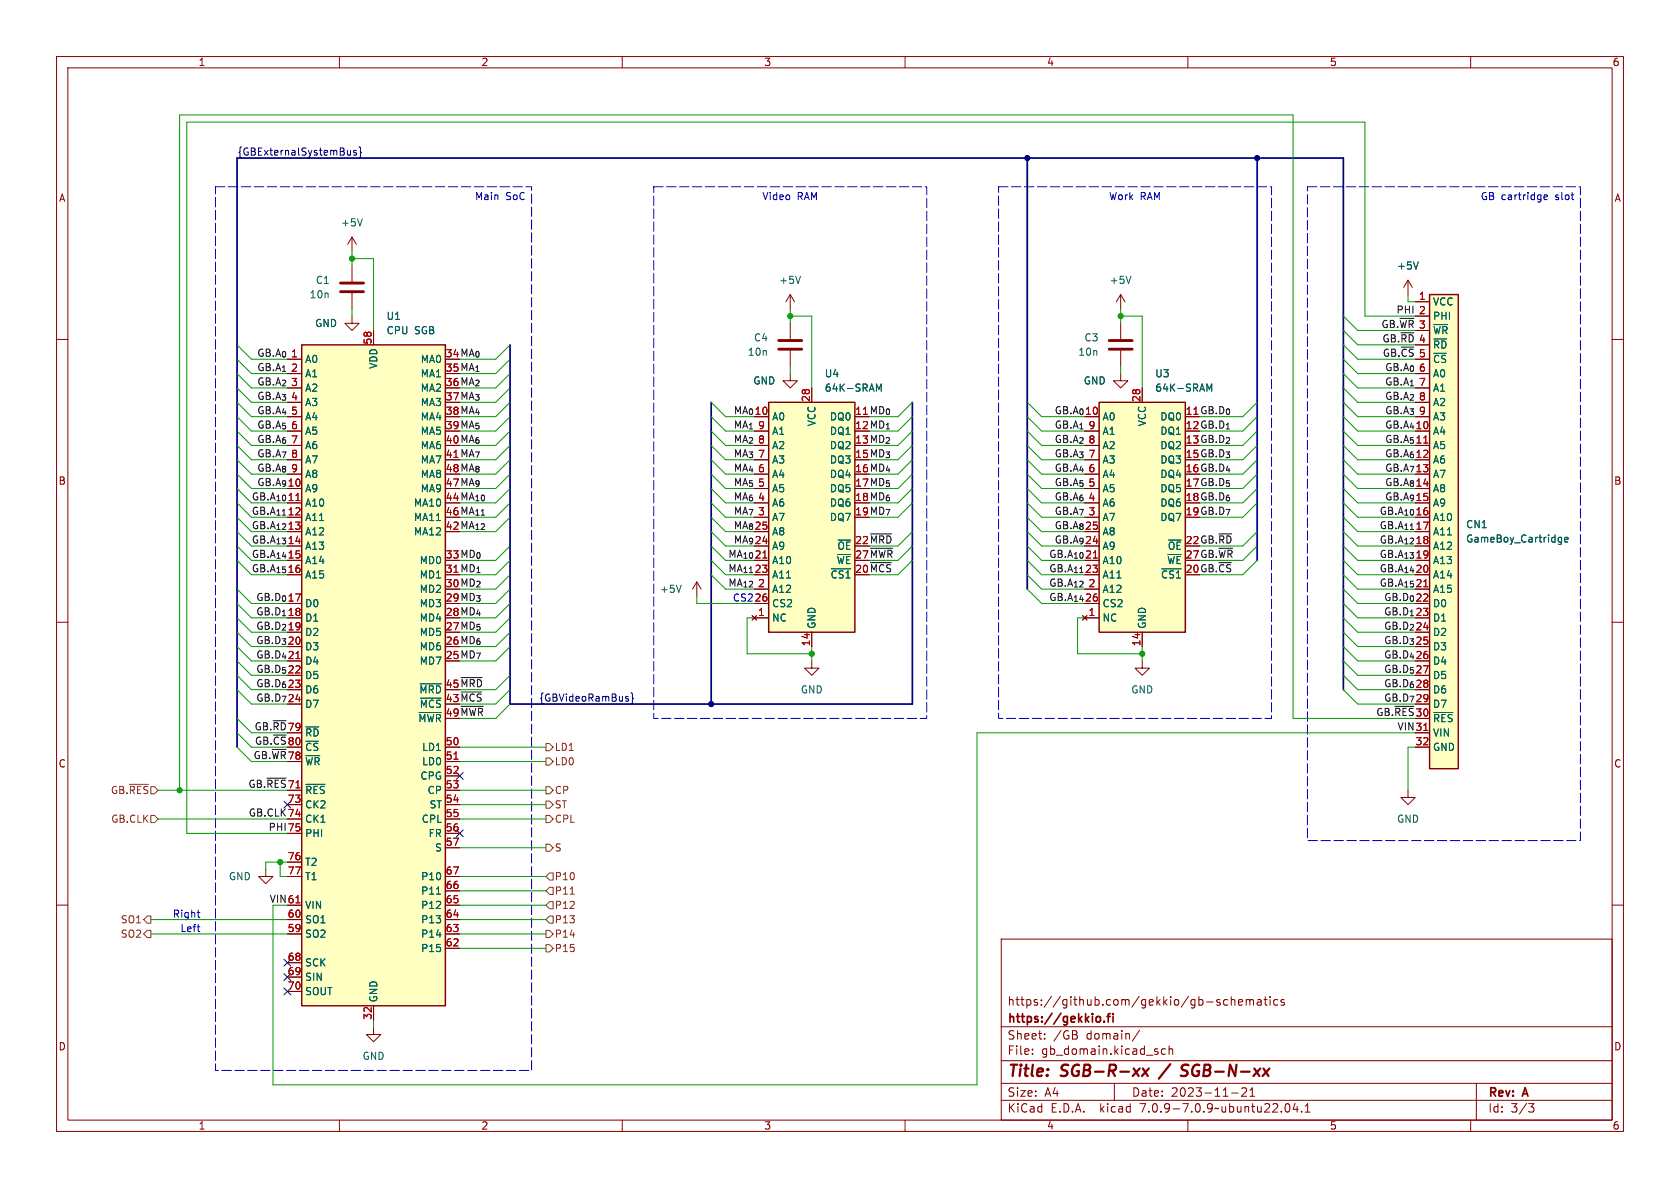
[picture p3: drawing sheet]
<svg xmlns="http://www.w3.org/2000/svg" width="297mm" height="210mm" viewBox="0 0 297 210" stroke-linecap="round" stroke-linejoin="round" font-family="sans-serif">
<defs><g id="words">
<g font-size="2.8" fill="#840000">
<text x="178" y="190.9">Title:</text>
<text x="187.7" y="190.9">SGB-R-xx</text>
<text x="210.5" y="190.9">SGB-N-xx</text>
</g>
<g font-size="2.1" fill="#840000">
<text x="178" y="178">https://github.com/gekkio/gb-schematics</text>
<text x="178" y="184">Sheet:</text>
<text x="178" y="181.2">https://gekkio.fi</text>
<text x="186.2" y="184">/GB</text>
<text x="192.1" y="184">domain/</text>
<text x="178" y="186.7">File:</text>
<text x="184.1" y="186.7">gb_domain.kicad_sch</text>
<text x="178" y="196.9">KiCad</text>
<text x="178" y="194.1">Size:</text>
<text x="184.7" y="194.1">A4</text>
<text x="185.7" y="196.9">E.D.A.</text>
<text x="194.6" y="196.9">kicad</text>
<text x="200" y="194.1">Date:</text>
<text x="201.8" y="196.9">7.0.9-7.0.9~ubuntu22.04.1</text>
<text x="207" y="194.1">2023-11-21</text>
<text x="263" y="194.3">Rev:</text>
<text x="263" y="196.9">Id:</text>
<text x="267.1" y="196.9">3/3</text>
<text x="269.4" y="194.3">A</text>
</g>
<g font-size="1.8" fill="#840000">
<text x="35" y="11.9">1</text>
<text x="85" y="11.9">2</text>
<text x="135" y="11.9">3</text>
<text x="185" y="11.9">4</text>
<text x="235" y="11.9">5</text>
<text x="285" y="11.9">6</text>
<text x="10.3" y="35.9">A</text>
<text x="285.3" y="35.9">A</text>
<text x="244.1" y="58.1">GB.~{WR}</text>
<text x="78.7" y="63.2">34 MA_{0}</text>
<text x="78.7" y="65.8">35 MA_{1}</text>
<text x="78.7" y="68.3">36 MA_{2}</text>
<text x="78.7" y="70.9">37 MA_{3}</text>
<text x="78.7" y="73.4">38 MA_{4}</text>
<text x="78.7" y="75.9">39 MA_{5}</text>
<text x="129.6" y="75.9">MA_{1}</text>
<text x="129.6" y="73.3">MA_{0}</text>
<text x="151.1" y="75.9">12 MD_{1}</text>
<text x="209.5" y="75.9">12 GB.D_{1}</text>
<text x="78.7" y="78.5">40 MA_{6}</text>
<text x="78.7" y="83.6">48 MA_{8}</text>
<text x="129.6" y="80.9">MA_{3}</text>
<text x="129.6" y="83.5">MA_{4}</text>
<text x="129.6" y="78.4">MA_{2}</text>
<text x="151.1" y="78.5">13 MD_{2}</text>
<text x="151.1" y="81">15 MD_{3}</text>
<text x="151.1" y="83.6">16 MD_{4}</text>
<text x="209.5" y="78.5">13 GB.D_{2}</text>
<text x="209.5" y="81">15 GB.D_{3}</text>
<text x="209.5" y="83.6">16 GB.D_{4}</text>
<text x="10.3" y="85.9">B</text>
<text x="78.7" y="88.6">44 MA_{10}</text>
<text x="78.7" y="86.1">47 MA_{9}</text>
<text x="129.6" y="86">MA_{5}</text>
<text x="129.6" y="88.6">MA_{6}</text>
<text x="151.1" y="86.1">17 MD_{5}</text>
<text x="151.1" y="88.6">18 MD_{6}</text>
<text x="209.5" y="86.1">17 GB.D_{5}</text>
<text x="209.5" y="88.6">18 GB.D_{6}</text>
<text x="285.3" y="85.9">B</text>
<text x="78.7" y="93.7">42 MA_{12}</text>
<text x="78.7" y="91.2">46 MA_{11}</text>
<text x="129.6" y="91.1">MA_{7}</text>
<text x="129.6" y="93.6">MA_{8}</text>
<text x="151.1" y="91.2">19 MD_{7}</text>
<text x="209.5" y="91.2">19 GB.D_{7}</text>
<text x="78.7" y="98.8">33 MD_{0}</text>
<text x="128.6" y="101.3">MA_{11}</text>
<text x="129.6" y="96.2">MA_{9}</text>
<text x="151.1" y="101.3">20 ~{MCS}</text>
<text x="151.1" y="96.3">22 ~{MRD}</text>
<text x="151.1" y="98.8">27 ~{MWR}</text>
<text x="209.5" y="101.3">20 GB.~{CS}</text>
<text x="209.5" y="96.3">22 GB.~{RD}</text>
<text x="209.5" y="98.8">27 GB.~{WR}</text>
<text x="78.7" y="106.4">29 MD_{3}</text>
<text x="78.7" y="103.9">30 MD_{2}</text>
<text x="128.6" y="103.8">MA_{12}</text>
<text x="78.7" y="111.5">27 MD_{5}</text>
<text x="78.7" y="109">28 MD_{4}</text>
<text x="78.7" y="116.6">25 MD_{7}</text>
<text x="78.7" y="114">26 MD_{6}</text>
<text x="78.7" y="124.2">43 ~{MCS}</text>
<text x="78.7" y="121.7">45 ~{MRD}</text>
<text x="78.7" y="126.7">49 ~{MWR}</text>
<text x="10.3" y="135.9">C</text>
<text x="44.7" y="134.3">GB.~{WR}</text>
<text x="285.3" y="135.9">C</text>
<text x="10.3" y="185.9">D</text>
<text x="285.3" y="185.9">D</text>
<text x="35" y="199.9">1</text>
<text x="85" y="199.9">2</text>
<text x="135" y="199.9">3</text>
<text x="185" y="199.9">4</text>
<text x="235" y="199.9">5</text>
<text x="285" y="199.9">6</text>
</g>
<g font-size="1.8" fill="#000084">
<text x="41.9" y="27.6">{GBExternalSystemBus}</text>
<text x="95.2" y="124.1">{GBVideoRamBus}</text>
</g>
<g font-size="1.8" fill="#0000c2">
<text x="83.9" y="35.7">Main</text>
<text x="89.4" y="35.7">SoC</text>
<text x="134.7" y="35.7">Video</text>
<text x="140.9" y="35.7">RAM</text>
<text x="196" y="35.7">Work</text>
<text x="201.5" y="35.7">RAM</text>
<text x="261.7" y="35.7">GB cartridge</text>
<text x="275.1" y="35.7">slot</text>
<text x="129.5" y="106.4">CS2</text>
<text x="30.5" y="162.3">Right</text>
<text x="31.8" y="164.9">Left</text>
</g>
<g font-size="1.8" fill="#006464">
<text x="60.2" y="40.2">+5V</text>
<text x="246.9" y="47.9">+5V</text>
<text x="54.6" y="52.9">10n</text>
<text x="55.7" y="50.4">C1</text>
<text x="137.7" y="50.4">+5V</text>
<text x="196.1" y="50.4">+5V</text>
<text x="55.6" y="58">GND</text>
<text x="68.2" y="56.7">U1</text>
<text x="68.2" y="59.3">CPU</text>
<text x="73.3" y="59.3">SGB</text>
<text x="253.2" y="54.2">VCC</text>
<text x="253.2" y="56.7">PHI</text>
<text x="253.2" y="59.3">~{WR}</text>
<text x="53.8" y="64.4">A0</text>
<text x="66.9" y="65.3" transform="rotate(-90 66.9 65.3)">VDD</text>
<text x="74.3" y="64.4">MA0</text>
<text x="132.1" y="63.1">10n</text>
<text x="133.2" y="60.6">C4</text>
<text x="190.5" y="63.1">10n</text>
<text x="191.6" y="60.6">C3</text>
<text x="253.2" y="61.8">~{RD}</text>
<text x="253.2" y="64.4">~{CS}</text>
<text x="53.8" y="66.9">A1</text>
<text x="53.8" y="69.4">A2</text>
<text x="53.8" y="72">A3</text>
<text x="74.3" y="66.9">MA1</text>
<text x="74.3" y="69.4">MA2</text>
<text x="74.3" y="72">MA3</text>
<text x="133.1" y="68.2">GND</text>
<text x="145.7" y="66.9">U4</text>
<text x="145.7" y="69.4">64K-SRAM</text>
<text x="191.5" y="68.2">GND</text>
<text x="204.1" y="66.9">U3</text>
<text x="204.1" y="69.4">64K-SRAM</text>
<text x="253.2" y="66.9">A0</text>
<text x="253.2" y="69.4">A1</text>
<text x="253.2" y="72">A2</text>
<text x="53.8" y="74.5">A4</text>
<text x="53.8" y="77.1">A5</text>
<text x="74.3" y="74.5">MA4</text>
<text x="74.3" y="77.1">MA5</text>
<text x="136.4" y="74.5">A0</text>
<text x="136.4" y="77.1">A1</text>
<text x="144.4" y="75.5" transform="rotate(-90 144.4 75.5)">VCC</text>
<text x="146.6" y="74.5">DQ0</text>
<text x="146.6" y="77.1">DQ1</text>
<text x="194.8" y="74.5">A0</text>
<text x="194.8" y="77.1">A1</text>
<text x="202.8" y="75.5" transform="rotate(-90 202.8 75.5)">VCC</text>
<text x="205" y="74.5">DQ0</text>
<text x="205" y="77.1">DQ1</text>
<text x="253.2" y="77.1">A4</text>
<text x="253.2" y="74.5">A3</text>
<text x="53.8" y="79.6">A6</text>
<text x="53.8" y="82.1">A7</text>
<text x="74.3" y="79.6">MA6</text>
<text x="74.3" y="82.1">MA7</text>
<text x="136.4" y="82.1">A3</text>
<text x="136.4" y="79.6">A2</text>
<text x="146.6" y="79.6">DQ2</text>
<text x="146.6" y="82.1">DQ3</text>
<text x="194.8" y="82.1">A3</text>
<text x="194.8" y="79.6">A2</text>
<text x="205" y="79.6">DQ2</text>
<text x="205" y="82.1">DQ3</text>
<text x="253.2" y="79.6">A5</text>
<text x="253.2" y="82.1">A6</text>
<text x="53.8" y="87.2">A9</text>
<text x="53.8" y="89.8">A10</text>
<text x="53.8" y="84.7">A8</text>
<text x="73.1" y="89.8">MA10</text>
<text x="74.3" y="87.2">MA9</text>
<text x="74.3" y="84.7">MA8</text>
<text x="136.4" y="89.8">A6</text>
<text x="136.4" y="87.2">A5</text>
<text x="136.4" y="84.7">A4</text>
<text x="146.6" y="84.7">DQ4</text>
<text x="146.6" y="87.2">DQ5</text>
<text x="146.6" y="89.8">DQ6</text>
<text x="194.8" y="89.8">A6</text>
<text x="194.8" y="87.2">A5</text>
<text x="194.8" y="84.7">A4</text>
<text x="205" y="84.7">DQ4</text>
<text x="205" y="87.2">DQ5</text>
<text x="205" y="89.8">DQ6</text>
<text x="253.2" y="84.7">A7</text>
<text x="253.2" y="87.2">A8</text>
<text x="253.2" y="89.8">A9</text>
<text x="53.8" y="92.3">A11</text>
<text x="53.8" y="94.8">A12</text>
<text x="73.1" y="94.8">MA12</text>
<text x="73.1" y="92.3">MA11</text>
<text x="136.4" y="94.8">A8</text>
<text x="136.4" y="92.3">A7</text>
<text x="146.6" y="92.3">DQ7</text>
<text x="194.8" y="94.8">A8</text>
<text x="194.8" y="92.3">A7</text>
<text x="205" y="92.3">DQ7</text>
<text x="253.2" y="92.3">A10</text>
<text x="253.2" y="94.8">A11</text>
<text x="259.1" y="93.6">CN1</text>
<text x="53.8" y="97.4">A13</text>
<text x="53.8" y="99.9">A14</text>
<text x="74.1" y="99.9">MD0</text>
<text x="136.4" y="99.9">A10</text>
<text x="136.4" y="97.4">A9</text>
<text x="147.8" y="99.9">~{WE}</text>
<text x="147.9" y="97.4">~{OE}</text>
<text x="194.8" y="99.9">A10</text>
<text x="194.8" y="97.4">A9</text>
<text x="206.2" y="99.9">~{WE}</text>
<text x="206.4" y="97.4">~{OE}</text>
<text x="253.2" y="97.4">A12</text>
<text x="253.2" y="99.9">A13</text>
<text x="259.1" y="96.1">GameBoy_Cartridge</text>
<text x="53.8" y="102.5">A15</text>
<text x="53.8" y="107.5">D0</text>
<text x="74.1" y="107.5">MD3</text>
<text x="74.1" y="105">MD2</text>
<text x="74.1" y="102.5">MD1</text>
<text x="116.6" y="105">+5V</text>
<text x="136.4" y="105">A12</text>
<text x="136.4" y="102.5">A11</text>
<text x="136.4" y="107.5">CS2</text>
<text x="146.7" y="102.5">~{CS1}</text>
<text x="194.8" y="105">A12</text>
<text x="194.8" y="102.5">A11</text>
<text x="194.8" y="107.5">CS2</text>
<text x="205.1" y="102.5">~{CS1}</text>
<text x="253.2" y="102.5">A14</text>
<text x="253.2" y="105">A15</text>
<text x="253.2" y="107.5">D0</text>
<text x="53.8" y="110.1">D1</text>
<text x="53.8" y="112.6">D2</text>
<text x="74.1" y="112.6">MD5</text>
<text x="74.1" y="110.1">MD4</text>
<text x="136.4" y="110.1">NC</text>
<text x="144.4" y="111.3" transform="rotate(-90 144.4 111.3)">GND</text>
<text x="194.8" y="110.1">NC</text>
<text x="202.8" y="111.3" transform="rotate(-90 202.8 111.3)">GND</text>
<text x="253.2" y="110.1">D1</text>
<text x="253.2" y="112.6">D2</text>
<text x="53.8" y="115.2">D3</text>
<text x="53.8" y="117.7">D4</text>
<text x="74.1" y="117.7">MD7</text>
<text x="74.1" y="115.2">MD6</text>
<text x="253.2" y="115.2">D3</text>
<text x="253.2" y="117.7">D4</text>
<text x="53.8" y="120.2">D5</text>
<text x="53.8" y="122.8">D6</text>
<text x="53.8" y="125.3">D7</text>
<text x="74" y="122.8">~{MRD}</text>
<text x="74.1" y="125.3">~{MCS}</text>
<text x="141.5" y="122.8">GND</text>
<text x="199.9" y="122.8">GND</text>
<text x="253.2" y="120.2">D5</text>
<text x="253.2" y="122.8">D6</text>
<text x="253.2" y="125.3">D7</text>
<text x="53.8" y="130.4">~{RD}</text>
<text x="73.9" y="127.9">~{MWR}</text>
<text x="253.2" y="127.9">~{RES}</text>
<text x="253.2" y="130.4">VIN</text>
<text x="53.8" y="135.5">~{WR}</text>
<text x="53.8" y="132.9">~{CS}</text>
<text x="74.5" y="132.9">LD1</text>
<text x="74.5" y="135.5">LD0</text>
<text x="253.2" y="132.9">GND</text>
<text x="53.8" y="140.6">~{RES}</text>
<text x="53.8" y="143.1">CK2</text>
<text x="74.2" y="138">CPG</text>
<text x="75.5" y="140.6">CP</text>
<text x="75.9" y="143.1">ST</text>
<text x="53.8" y="145.6">CK1</text>
<text x="53.8" y="148.2">PHI</text>
<text x="74.5" y="145.6">CPL</text>
<text x="75.7" y="148.2">FR</text>
<text x="246.9" y="145.6">GND</text>
<text x="40.4" y="155.8">GND</text>
<text x="53.8" y="153.3">T2</text>
<text x="53.8" y="155.8">T1</text>
<text x="74.3" y="155.8">P10</text>
<text x="76.8" y="150.7">S</text>
<text x="53.8" y="160.9">VIN</text>
<text x="74.3" y="160.9">P12</text>
<text x="74.3" y="158.3">P11</text>
<text x="53.8" y="166">SO2</text>
<text x="53.8" y="163.4">SO1</text>
<text x="74.3" y="166">P14</text>
<text x="74.3" y="163.4">P13</text>
<text x="53.8" y="171">SCK</text>
<text x="53.8" y="173.6">SIN</text>
<text x="74.3" y="168.5">P15</text>
<text x="53.8" y="176.1">SOUT</text>
<text x="66.9" y="177.3" transform="rotate(-90 66.9 177.3)">GND</text>
<text x="64" y="187.6">GND</text>
</g>
<g font-size="1.8" fill="#a90000">
<text x="250.8" y="53.1">1</text>
<text x="250.8" y="58.2">3</text>
<text x="250.8" y="55.6">2</text>
<text x="51.4" y="63.2">1</text>
<text x="51.4" y="65.8">2</text>
<text x="65.8" y="61" transform="rotate(-90 65.8 61)">58</text>
<text x="78.7" y="63.2">34</text>
<text x="78.7" y="65.8">35</text>
<text x="250.8" y="60.7">4</text>
<text x="250.8" y="63.2">5</text>
<text x="250.8" y="65.8">6</text>
<text x="51.4" y="68.3">3</text>
<text x="51.4" y="70.9">4</text>
<text x="78.7" y="68.3">36</text>
<text x="78.7" y="70.9">37</text>
<text x="143.3" y="71.2" transform="rotate(-90 143.3 71.2)">28</text>
<text x="201.7" y="71.2" transform="rotate(-90 201.7 71.2)">28</text>
<text x="250.8" y="68.3">7</text>
<text x="250.8" y="70.9">8</text>
<text x="51.4" y="73.4">5</text>
<text x="51.4" y="75.9">6</text>
<text x="78.7" y="73.4">38</text>
<text x="78.7" y="75.9">39</text>
<text x="133.3" y="73.4">10</text>
<text x="133.9" y="75.9">9</text>
<text x="151.1" y="73.4">11 MD_{0}</text>
<text x="151.1" y="73.4">11</text>
<text x="151.1" y="75.9">12</text>
<text x="191.7" y="73.4">10</text>
<text x="192.3" y="75.9">9</text>
<text x="209.5" y="73.4">11 GB.D_{0}</text>
<text x="209.5" y="73.4">11</text>
<text x="209.5" y="75.9">12</text>
<text x="250.1" y="75.9">10</text>
<text x="250.8" y="73.4">9</text>
<text x="51.4" y="78.5">7</text>
<text x="51.4" y="81">8</text>
<text x="51.4" y="83.6">9</text>
<text x="78.7" y="81">41 MA_{7}</text>
<text x="78.7" y="78.5">40</text>
<text x="78.7" y="81">41</text>
<text x="78.7" y="83.6">48</text>
<text x="133.9" y="83.6">6</text>
<text x="133.9" y="81">7</text>
<text x="133.9" y="78.5">8</text>
<text x="151.1" y="78.5">13</text>
<text x="151.1" y="81">15</text>
<text x="151.1" y="83.6">16</text>
<text x="192.3" y="83.6">6</text>
<text x="192.3" y="81">7</text>
<text x="192.3" y="78.5">8</text>
<text x="209.5" y="78.5">13</text>
<text x="209.5" y="81">15</text>
<text x="209.5" y="83.6">16</text>
<text x="244.7" y="78.4">GB.A_{5}</text>
<text x="250.1" y="78.5">11</text>
<text x="250.1" y="81">12</text>
<text x="250.1" y="83.6">13</text>
<text x="44.4" y="88.6">GB.A_{10}</text>
<text x="50.8" y="86.1">10</text>
<text x="50.8" y="88.6">11</text>
<text x="78.7" y="88.6">44</text>
<text x="78.7" y="86.1">47</text>
<text x="133.9" y="88.6">4</text>
<text x="133.9" y="86.1">5</text>
<text x="151.1" y="86.1">17</text>
<text x="151.1" y="88.6">18</text>
<text x="192.3" y="88.6">4</text>
<text x="192.3" y="86.1">5</text>
<text x="209.5" y="86.1">17</text>
<text x="209.5" y="88.6">18</text>
<text x="250.1" y="86.1">14</text>
<text x="250.1" y="88.6">15</text>
<text x="50.8" y="91.2">12</text>
<text x="50.8" y="93.7">13</text>
<text x="78.7" y="93.7">42</text>
<text x="78.7" y="91.2">46</text>
<text x="133.3" y="93.7">25</text>
<text x="133.9" y="91.2">3</text>
<text x="151.1" y="91.2">19</text>
<text x="191.7" y="93.7">25</text>
<text x="192.3" y="91.2">3</text>
<text x="209.5" y="91.2">19</text>
<text x="250.1" y="91.2">16</text>
<text x="250.1" y="93.7">17</text>
<text x="50.8" y="96.3">14</text>
<text x="50.8" y="98.8">15</text>
<text x="50.8" y="101.3">16</text>
<text x="78.7" y="101.3">31 MD_{1}</text>
<text x="78.7" y="101.3">31</text>
<text x="78.7" y="98.8">33</text>
<text x="128.6" y="98.7">MA_{10}</text>
<text x="133.3" y="98.8">21</text>
<text x="133.3" y="101.3">23</text>
<text x="133.3" y="96.3">24</text>
<text x="151.1" y="101.3">20</text>
<text x="151.1" y="96.3">22</text>
<text x="151.1" y="98.8">27</text>
<text x="185.3" y="98.7">GB.A_{10}</text>
<text x="191.7" y="98.8">21</text>
<text x="191.7" y="101.3">23</text>
<text x="191.7" y="96.3">24</text>
<text x="209.5" y="101.3">20</text>
<text x="209.5" y="96.3">22</text>
<text x="209.5" y="98.8">27</text>
<text x="250.1" y="96.3">18</text>
<text x="250.1" y="98.8">19</text>
<text x="250.1" y="101.3">20</text>
<text x="50.8" y="106.4">17</text>
<text x="78.7" y="106.4">29</text>
<text x="78.7" y="103.9">30</text>
<text x="133.3" y="106.4">26</text>
<text x="133.9" y="103.9">2</text>
<text x="191.7" y="106.4">26</text>
<text x="192.3" y="103.9">2</text>
<text x="243.8" y="103.8">GB.A_{15}</text>
<text x="250.1" y="103.9">21</text>
<text x="250.1" y="106.4">22</text>
<text x="50.8" y="109">18</text>
<text x="50.8" y="111.5">19</text>
<text x="78.7" y="111.5">27</text>
<text x="78.7" y="109">28</text>
<text x="133.9" y="109">1</text>
<text x="192.3" y="109">1</text>
<text x="250.1" y="109">23</text>
<text x="250.1" y="111.5">24</text>
<text x="45.2" y="116.5">GB.D_{4}</text>
<text x="50.8" y="114">20</text>
<text x="50.8" y="116.6">21</text>
<text x="50.8" y="119.1">22</text>
<text x="78.7" y="116.6">25</text>
<text x="78.7" y="114">26</text>
<text x="143.3" y="114.3" transform="rotate(-90 143.3 114.3)">14</text>
<text x="201.7" y="114.3" transform="rotate(-90 201.7 114.3)">14</text>
<text x="250.1" y="114">25</text>
<text x="250.1" y="116.6">26</text>
<text x="250.1" y="119.1">27</text>
<text x="50.8" y="121.7">23</text>
<text x="50.8" y="124.2">24</text>
<text x="78.7" y="124.2">43</text>
<text x="78.7" y="121.7">45</text>
<text x="250.1" y="121.7">28</text>
<text x="250.1" y="124.2">29</text>
<text x="50.8" y="129.3">79</text>
<text x="50.8" y="131.8">80</text>
<text x="78.7" y="131.8">50</text>
<text x="78.7" y="126.7">49</text>
<text x="250.1" y="126.7">30</text>
<text x="250.1" y="131.8">32</text>
<text x="250.1" y="129.3">31</text>
<text x="50.8" y="134.4">78</text>
<text x="78.7" y="134.4">51</text>
<text x="78.7" y="136.9">52</text>
<text x="43.8" y="139.4">GB.~{RES}</text>
<text x="50.8" y="139.4">71</text>
<text x="50.8" y="142">73</text>
<text x="78.7" y="139.4">53</text>
<text x="78.7" y="142">54</text>
<text x="50.8" y="144.5">74</text>
<text x="50.8" y="147.1">75</text>
<text x="78.7" y="144.5">55</text>
<text x="78.7" y="147.1">56</text>
<text x="78.7" y="149.6">57</text>
<text x="50.8" y="152.1">76</text>
<text x="50.8" y="154.7">77</text>
<text x="78.7" y="154.7">67</text>
<text x="50.8" y="159.8">61</text>
<text x="78.7" y="159.8">65</text>
<text x="78.7" y="157.2">66</text>
<text x="50.8" y="164.8">59</text>
<text x="50.8" y="162.3">60</text>
<text x="78.7" y="167.4">62</text>
<text x="78.7" y="164.8">63</text>
<text x="78.7" y="162.3">64</text>
<text x="50.8" y="169.9">68</text>
<text x="50.8" y="172.5">69</text>
<text x="50.8" y="175">70</text>
<text x="65.8" y="180.4" transform="rotate(-90 65.8 180.4)">32</text>
</g>
<g font-size="1.8" fill="#0f0f0f">
<text x="246.8" y="55.5">PHI 2</text>
<text x="45.3" y="65.7">GB.A_{1}</text>
<text x="45.3" y="63.2">GB.A_{0}</text>
<text x="244.3" y="60.6">GB.~{RD}</text>
<text x="244.4" y="63.2">GB.~{CS}</text>
<text x="244.7" y="65.7">GB.A_{0}</text>
<text x="45.3" y="68.2">GB.A_{2}</text>
<text x="45.3" y="70.8">GB.A_{3}</text>
<text x="244.7" y="70.8">GB.A_{2}</text>
<text x="244.7" y="68.2">GB.A_{1}</text>
<text x="45.3" y="75.9">GB.A_{5}</text>
<text x="45.3" y="73.3">GB.A_{4}</text>
<text x="186.3" y="75.9">GB.A_{1}</text>
<text x="186.3" y="73.3">GB.A_{0}</text>
<text x="244.7" y="73.3">GB.A_{3}</text>
<text x="244.7" y="75.9">GB.A_{4}</text>
<text x="45.3" y="80.9">GB.A_{7}</text>
<text x="45.3" y="78.4">GB.A_{6}</text>
<text x="45.3" y="83.5">GB.A_{8}</text>
<text x="186.3" y="80.9">GB.A_{3}</text>
<text x="186.3" y="78.4">GB.A_{2}</text>
<text x="186.3" y="83.5">GB.A_{4}</text>
<text x="244.7" y="83.5">GB.A_{7}</text>
<text x="244.7" y="80.9">GB.A_{6}</text>
<text x="45.3" y="86">GB.A_{9}</text>
<text x="186.3" y="86">GB.A_{5}</text>
<text x="186.3" y="88.6">GB.A_{6}</text>
<text x="244.7" y="88.6">GB.A_{9}</text>
<text x="244.7" y="86">GB.A_{8}</text>
<text x="44.4" y="93.6">GB.A_{12}</text>
<text x="44.4" y="91.1">GB.A_{11}</text>
<text x="186.3" y="93.6">GB.A_{8}</text>
<text x="186.3" y="91.1">GB.A_{7}</text>
<text x="243.8" y="93.6">GB.A_{11}</text>
<text x="243.8" y="91.1">GB.A_{10}</text>
<text x="44.4" y="98.7">GB.A_{14}</text>
<text x="44.4" y="101.3">GB.A_{15}</text>
<text x="44.4" y="96.2">GB.A_{13}</text>
<text x="185.3" y="101.3">GB.A_{11}</text>
<text x="186.3" y="96.2">GB.A_{9}</text>
<text x="243.8" y="101.3">GB.A_{14}</text>
<text x="243.8" y="96.2">GB.A_{12}</text>
<text x="243.8" y="98.7">GB.A_{13}</text>
<text x="45.2" y="106.3">GB.D_{0}</text>
<text x="185.3" y="106.3">GB.A_{14}</text>
<text x="185.3" y="103.8">GB.A_{12}</text>
<text x="244.6" y="106.3">GB.D_{0}</text>
<text x="45.2" y="108.9">GB.D_{1}</text>
<text x="45.2" y="114">GB.D_{3}</text>
<text x="45.2" y="111.4">GB.D_{2}</text>
<text x="244.6" y="114">GB.D_{3}</text>
<text x="244.6" y="108.9">GB.D_{1}</text>
<text x="244.6" y="111.4">GB.D_{2}</text>
<text x="45.2" y="119">GB.D_{5}</text>
<text x="244.6" y="116.5">GB.D_{4}</text>
<text x="244.6" y="119">GB.D_{5}</text>
<text x="45.2" y="124.1">GB.D_{7}</text>
<text x="45.2" y="121.6">GB.D_{6}</text>
<text x="244.6" y="124.1">GB.D_{7}</text>
<text x="244.6" y="121.6">GB.D_{6}</text>
<text x="44.9" y="129.2">GB.~{RD}</text>
<text x="45" y="131.7">GB.~{CS}</text>
<text x="243.2" y="126.7">GB.~{RES}</text>
<text x="247" y="129.2">VIN31</text>
<text x="43.9" y="144.4">GB.CLK 74</text>
<text x="47.4" y="147">PHI 75</text>
</g>
<g font-size="1.8" fill="#725600">
<text x="98" y="135.5">LD0</text>
<text x="98" y="132.9">LD1</text>
<text x="19.5" y="140.6">GB.~{RES}</text>
<text x="98" y="140.6">CP</text>
<text x="98" y="143.1">ST</text>
<text x="19.6" y="145.6">GB.CLK</text>
<text x="98" y="145.6">CPL</text>
<text x="98" y="150.7">S</text>
<text x="98" y="155.8">P10</text>
<text x="98" y="158.3">P11</text>
<text x="98" y="160.9">P12</text>
<text x="21.3" y="163.4">SO1</text>
<text x="21.3" y="166">SO2</text>
<text x="98" y="163.4">P13</text>
<text x="98" y="166">P14</text>
<text x="98" y="168.5">P15</text>
</g>
<text font-size="1.8" fill="#009600" x="47.6" y="159.7">VIN61</text>
</g></defs>
<g fill="none" stroke="#840000" stroke-width=".18">
<path d="M10 10h277v190h-277zM12 12h273v186h-273zM60 10v2M110 10v2M160 10v2M210 10v2M260 10v2M10 60h2M62.2 55.9v1.3h1.3l-1.3 1.2-1.2-1.2h1.2M62.2 41.9l-.7 1.3M62.2 41.9v2.6M62.2 47v2.8"/>
<path d="M62.2 51.8v2.8M62.2 41.9l.8 1.3M66 58.4v2.6M139.7 52.1v2.5M139.7 57.2v2.7M139.7 52.1l-.8 1.2M139.7 52.1l.8 1.2M198.1 52.1l-.7 1.2M198.1 52.1v2.5M198.1 57.2v2.7M198.1 52.1l.8 1.2M248.9 49.5l-.7 1.3"/>
<path d="M248.9 49.5v2.6M248.9 49.5l.8 1.3M250.2 53.3h2.5M250.2 55.9h2.5M285 60h2M50.8 73.7h2.5M50.8 78.7h2.5M50.8 76.2h2.5M50.8 63.5h2.5M50.8 66h2.5M50.8 68.6h2.5M50.8 71.1h2.5"/>
<path d="M139.7 66v1.3h1.3l-1.3 1.3-1.3-1.3h1.3M139.7 62v2.8M143.5 68.6v2.5M191.8 73.7h2.5M191.8 78.7h2.5M191.8 76.2h2.5M198.1 66v1.3h1.3l-1.3 1.3-1.3-1.3h1.3M198.1 62v2.8M201.9 68.6v2.5M250.2 73.7h2.5M250.2 78.7h2.5M250.2 76.2h2.5"/>
<path d="M250.2 63.5h2.5M250.2 66h2.5M250.2 68.6h2.5M250.2 71.1h2.5M250.2 61h2.5M50.8 99.1h2.5M50.8 96.5h2.5M50.8 94h2.5M50.8 91.4h2.5M50.8 88.9h2.5M50.8 86.4h2.5M50.8 83.8h2.5"/>
<path d="M50.8 81.3h2.5M191.8 99.1h2.5M191.8 96.5h2.5M191.8 94h2.5M191.8 91.4h2.5M191.8 88.9h2.5M191.8 86.4h2.5M191.8 83.8h2.5M191.8 81.3h2.5M250.2 99.1h2.5M250.2 96.5h2.5M250.2 94h2.5"/>
<path d="M250.2 91.4h2.5M250.2 88.9h2.5M250.2 86.4h2.5M250.2 83.8h2.5M250.2 81.3h2.5M10 110h2M50.8 109.2h2.5M50.8 101.6h2.5M50.8 106.7h2.5M50.8 111.8h2.5M50.8 114.3h2.5M50.8 116.8h2.5"/>
<path d="M50.8 119.4h2.5M123.2 102.9l-.8 1.2M123.2 102.9v2.5M123.2 102.9l.8 1.2M133 108.8l.7 .8M133.3 109.2h2.6M133.3 106.7h2.6M133.7 108.8l-.7 .8M143.5 116.8v1.3h1.3l-1.3 1.3-1.3-1.3h1.3M143.5 111.8v2.5M191.4 108.8l.8 .8M191.8 109.2h2.5"/>
<path d="M191.8 104.1h2.5M191.8 101.6h2.5M191.8 106.7h2.5M192.2 108.8l-.8 .8M201.9 116.8v1.3h1.3l-1.3 1.3-1.2-1.3h1.2M201.9 111.8v2.5M250.2 109.2h2.5M250.2 104.1h2.5M250.2 101.6h2.5M250.2 106.7h2.5M250.2 111.8h2.5M250.2 114.3h2.5"/>
<path d="M250.2 116.8h2.5M250.2 119.4h2.5M285 110h2M50.8 121.9h2.5M50.8 124.5h2.5M50.8 132.1h2.5M50.8 139.7h2.5M50.8 129.5h2.5M78.7 132.1h2.6M78.7 134.6h2.6M78.7 137.2h2.6M78.7 139.7h2.6"/>
<path d="M248.9 139.7v1.3h1.3l-1.3 1.2-1.3-1.2h1.3M250.2 121.9h2.5M250.2 124.5h2.5M250.2 132.1h2.5M250.2 129.5h2.5M250.2 127h2.5M10 160h2M47 153.7v1.2h1.3l-1.3 1.3-1.3-1.3h1.3M50.8 142.2h2.5M50.8 144.8h2.5M50.8 147.3h2.5M50.8 154.9h2.5"/>
<path d="M50.8 152.4h2.5M78.7 142.2h2.6M78.7 144.8h2.6M78.7 147.3h2.6M78.7 149.9h2.6M78.7 157.5h2.6M78.7 154.9h2.6M285 160h2M50.8 165.1h2.5M50.8 162.6h2.5M50.8 160h2.5M50.8 170.2h2.5"/>
<path d="M50.8 172.7h2.5M50.8 175.3h2.5M66 177.8v2.5M78.7 165.1h2.6M78.7 162.6h2.6M78.7 160h2.6M78.7 167.6h2.6M177 166h108v32h-108zM217 176.8l-.4-.1-.3 .3v.4l.2 .2h.5M217.7 176.8l.2-.1 .3 .1 .1 .9M217.7 176.2v1.5M219 177.2l.7-.1-.1-.3-.4-.1-.2 .2v.7h.6"/>
<path d="M220.3 176.8l.4-.1 .3 .2M220.3 176.7v1M221 176.9l.2-.2 .3 .1 .1 .9M221 176.9v.8M222.3 176.8h.6l.1 .9M223 177.1h-.5a.29 .29 0 0 0-.3 .3 .29 .29 0 0 0 .3 .3l.5-.1M223.5 176.7h.5M223.7 176.2v1.3l.3 .2M224.5 176.2v.1M224.5 176.7v1M225.9 176.8l-.4-.1-.3 .3v.4l.1 .2h.6M227 176.8l-.3-.1-.2 .2v.2l.5 .2v.3h-.5"/>
<path d="M60 198v2M66 181.6v1.3h1.3l-1.3 1.3-1.2-1.3h1.2M110 198v2M160 198v2M177 194.5h108M177 191.5h108M177 187.5h108M177 181.5h108M182.5 186.3v.1M182.5 185.5v.1M184.7 183.6v.1M184.7 182.8v.1"/>
<path d="M197 191.5v3M201.5 182.1l-1.3 2M206 185.5l-.4-.1-.3 .3v.4l.2 .2h.5M206.7 185.5l.2-.1 .3 .1 .1 .9M206.7 184.9v1.5M210 198v2M217.7 193.2h1.2M219.5 192.4l.6-.1 .2 .1 .1 .3-.9 1.1h.9M221 193.8h.8M221 192.7l.4-.4v1.5M227.3 195.2l.2-.1a.81 .81 0 0 1 .6 .6 .81 .81 0 0 1-.3 .8l-.1 .1a.81 .81 0 0 1-.4-1.4zM229 195l-.4 1.1h.9"/>
<path d="M229.3 195.6v1M230.1 196.5v.1M230.7 196.6h.9M230.7 195.5l.5-.4v1.5M260 198v2M261 191.5v6.5M270.2 195.1h1l-.5 .6 .4 .1 .1 .5-.3 .3h-.4"/>
</g>
<path d="M202 188.9l.9 1.3M203.1 188.9l-1.2 1.3M206.9 188.1l-2 2.6M209.8 190a.85 .85 0 0 1-1.1 .1M209.8 188.2l-.6 .1a.46 .46 0 0 0-.3 .5 .46 .46 0 0 0 .3 .4l.6 .2" fill="none" stroke="#840000" stroke-width=".4"/>
<path d="M193.9 179.8l.4-.1 .3 .3-.1 .5-.2 .2-.4-.1M195.7 179.7h.6M196.3 179.2l-.4 .2v1.3M196.8 179.2v.1M196.8 179.7v1M195.2 180.5v.2" fill="none" stroke="#840000" stroke-width=".3"/>
<g fill="#ffffc2" stroke="#ffffc2" stroke-width=".18">
<path d="M194.3 71.1h15.2v40.7h-15.2z"/>
<path d="M53.3 61h25.4v116.8h-25.4z"/>
<path d="M252.7 52.1h5.1v83.8h-5.1z"/>
<path d="M135.9 71.1h15.2v40.7h-15.2z"/>
</g>
<path d="M252.7 52.1h5.1v83.8h-5.1zM53.3 61h25.4v116.8h-25.4zM135.9 71.1h15.2v40.7h-15.2zM194.3 71.1h15.2v40.7h-15.2z" fill="none" stroke="#840000" stroke-width=".25"/>
<g fill="none" stroke="#006464" stroke-width=".18">
<path d="M64 38.7l-.4 1.2M141.5 48.8l-.4 1.3M199.9 48.8l-.4 1.3M250.7 46.3l-.4 1.3M253.5 57.4h2.4M154.9 67.9l.5 .9 .4-.9v1.3M213.4 67.9l.4 .9 .4-.9v1.3M275.7 95h.4M276.1 95v1l-.2 .2-.3 .1M276.1 95.8h-.4M276.6 95.4l.6-.1v-.3h-.4l-.2 .2 .1 .6h.5M120.4 103.4l-.4 1.3"/>
<path d="M147 100.6h3.4M205.4 100.6h3.4M54.1 138.7h3.3M54.1 128.5h2.3M74.1 126h3.9M74.3 120.9h3.7M74.3 123.4h3.7M253.5 126h3.3M77.2 158.1h.7"/>
</g>
<path d="M80.3 134.2h.7M251.7 129.1h.7M52.3 159.6h.7" fill="none" stroke="#a90000" stroke-width=".18"/>
<path d="M60.2 51.6h4.1M60.2 50h4.1M137.7 61.7h4M137.7 60.2h4M196.1 61.7h4.1M196.1 60.2h4.1" fill="none" stroke="#840000" stroke-width=".51"/>
<g fill="none" stroke="#725600" stroke-width=".18">
<path d="M22.9 138.7h3.4M96.5 134h.7l.6 .6-.6 .7h-.7zM96.5 139.1h.7l.6 .6-.6 .6h-.7zM96.5 131.4h.7l.6 .7-.6 .6h-.7zM26.7 144.1h.6l.6 .7-.6 .6h-.6zM96.5 144.1h.7l.6 .7-.6 .6h-.7zM96.5 149.2h.7l.6 .7-.6 .6h-.7zM96.5 141.6h.7l.6 .6-.6 .7h-.7zM97.2 156.8h.6v1.3h-.6l-.7-.6zM97.2 154.3h.6v1.3h-.6l-.7-.7zM97.2 159.4h.6v1.3h-.6l-.7-.7zM100.8 158.1h.7"/>
<path d="M26 161.9h.7v1.3h-.7l-.6-.6zM26 164.5h.7v1.2h-.7l-.6-.6zM96.5 164.5h.7l.6 .6-.6 .6h-.7zM96.5 167h.7l.6 .6-.6 .7h-.7zM97.2 161.9h.6v1.3h-.6l-.7-.6z"/>
</g>
<path d="M153.9 94.4h3.7M153.9 96.9h3.9M153.9 99.5h3.7M81.5 119.8h3.7M47.2 137.6h3.4M81.5 124.9h3.9M81.5 122.3h3.7M246.6 124.9h3.4" fill="none" stroke="#0f0f0f" stroke-width=".18"/>
<g fill="none" stroke="#000084" stroke-width=".18">
<path d="M62 26.6v.8M62 27.3l-.4 .1M63 26.6h-.3l-.2 .2 .1 .1 .4 .2v.3h-.5M63.5 26l.2 .2v.6l.2 .1-.2 .2v.6l-.2 .2M80.7 136.6l1.2 1.2M81.9 136.6l-1.2 1.2M110.8 123.5l.3 .1v.2l-.1 .1h-.3M110.8 123.1l.3 .1M111.6 122.5l.2 .2v.6l.2 .2-.2 .1v.6l-.2 .2M50.2 141.6l1.2 1.2M51.4 141.6l-1.2 1.2M80.7 146.7l1.2 1.2"/>
<path d="M81.9 146.7l-1.2 1.2M50.2 174.7l1.2 1.2M50.2 172.1l1.2 1.2M50.2 169.6l1.2 1.2M51.4 174.7l-1.2 1.2M51.4 172.1l-1.2 1.2M51.4 169.6l-1.2 1.2"/>
</g>
<path d="M273 34.9l.6-.1-.1-.3-.4-.1-.1 .2v.6h.5M34.9 161.3h.4M34.9 163.8h.4M35.1 162.1h.2M35.2 164.7h.1" fill="none" stroke="#0000c2" stroke-width=".18"/>
<path d="M38.1 33h55.9v156.2h-55.9zM115.6 33h48.2v94h-48.2zM176.5 33h48.3v94h-48.3zM231.1 33h48.3v115.6h-48.3z" fill="none" stroke="#0000c2" stroke-width=".18" stroke-dasharray="1.7 .6"/>
<path d="M181.6 27.9v76.2M222.2 27.9v71.2M90.2 61v63.5h71.1v-53.4M125.7 71.1v53.4M237.5 121.9v-94h-195.6v104.2" fill="none" stroke="#000084" stroke-width=".3"/>
<g fill="none" stroke="#009600" stroke-width=".18">
<path d="M62.2 44.5v2.5M62.2 54.6v1.3M62.2 45.7h3.8v12.7M139.7 55.9h3.8v12.7M139.7 54.6v2.6M198.1 55.9h3.8v12.7M198.1 54.6v2.6M237.5 55.9l2.5 2.5h10.2M237.5 58.4l2.5 2.6h10.2M248.9 52.1v1.2h1.3M250.2 55.9h-8.9v-34.3h-208.3v125.7h17.8M41.9 76.2l2.5 2.5h6.4"/>
<path d="M41.9 73.7l2.5 2.5h6.4M41.9 71.1l2.5 2.6h6.4M41.9 63.5l2.5 2.5h6.4M41.9 66l2.5 2.6h6.4M41.9 61l2.5 2.5h6.4M41.9 78.7l2.5 2.6h6.4M41.9 68.6l2.5 2.5h6.4M90.2 76.2l-2.6 2.5h-6.3M90.2 73.7l-2.6 2.5h-6.3M90.2 71.1l-2.6 2.6h-6.3M90.2 63.5l-2.6 2.5h-6.3M90.2 66l-2.6 2.6h-6.3"/>
<path d="M90.2 61l-2.6 2.5h-6.3M90.2 78.7l-2.6 2.6h-6.3M90.2 68.6l-2.6 2.5h-6.3M125.7 76.2l2.6 2.5h5M125.7 73.7l2.6 2.5h5M125.7 71.1l2.6 2.6h5M125.7 78.7l2.6 2.6h5M139.7 64.8v1.2M161.3 76.2l-2.6 2.5h-5M161.3 73.7l-2.6 2.5h-5M161.3 71.1l-2.6 2.6h-5M161.3 78.7l-2.6 2.6h-5"/>
<path d="M181.6 76.2l2.5 2.5h7.7M181.6 73.7l2.5 2.5h7.7M181.6 71.1l2.5 2.6h7.7M181.6 78.7l2.5 2.6h7.7M198.1 64.8v1.2M222.2 76.2l-2.5 2.5h-7.6M222.2 73.7l-2.5 2.5h-7.6M222.2 71.1l-2.5 2.6h-7.6M222.2 78.7l-2.5 2.6h-7.6M237.5 76.2l2.5 2.5h10.2M237.5 73.7l2.5 2.5h10.2M237.5 71.1l2.5 2.6h10.2"/>
<path d="M237.5 63.5l2.5 2.5h10.2M237.5 66l2.5 2.6h10.2M237.5 61l2.5 2.5h10.2M237.5 78.7l2.5 2.6h10.2M237.5 68.6l2.5 2.5h10.2M41.9 96.5l2.5 2.6h6.4M41.9 86.4l2.5 2.5h6.4M41.9 91.4l2.5 2.6h6.4M41.9 88.9l2.5 2.5h6.4M41.9 81.3l2.5 2.5h6.4M41.9 99.1l2.5 2.5h6.4M41.9 83.8l2.5 2.6h6.4"/>
<path d="M41.9 94l2.5 2.5h6.4M90.2 96.5l-2.6 2.6h-6.3M90.2 86.4l-2.6 2.5h-6.3M90.2 91.4l-2.6 2.6h-6.3M90.2 88.9l-2.6 2.5h-6.3M90.2 81.3l-2.6 2.5h-6.3M90.2 99.1l-2.6 2.5h-6.3M90.2 83.8l-2.6 2.6h-6.3M125.7 96.5l2.6 2.6h5M125.7 86.4l2.6 2.5h5M125.7 91.4l2.6 2.6h5M125.7 88.9l2.6 2.5h5"/>
<path d="M125.7 81.3l2.6 2.5h5M125.7 99.1l2.6 2.5h5M125.7 83.8l2.6 2.6h5M125.7 94l2.6 2.5h5M161.3 96.5l-2.6 2.6h-5M161.3 86.4l-2.6 2.5h-5M161.3 88.9l-2.6 2.5h-5M161.3 81.3l-2.6 2.5h-5M161.3 99.1l-2.6 2.5h-5M161.3 83.8l-2.6 2.6h-5M161.3 94l-2.6 2.5h-5M181.6 96.5l2.5 2.6h7.7"/>
<path d="M181.6 86.4l2.5 2.5h7.7M181.6 91.4l2.5 2.6h7.7M181.6 88.9l2.5 2.5h7.7M181.6 81.3l2.5 2.5h7.7M181.6 99.1l2.5 2.5h7.7M181.6 83.8l2.5 2.6h7.7M181.6 94l2.5 2.5h7.7M222.2 96.5l-2.5 2.6h-7.6M222.2 86.4l-2.5 2.5h-7.6M222.2 88.9l-2.5 2.5h-7.6M222.2 81.3l-2.5 2.5h-7.6M222.2 99.1l-2.5 2.5h-7.6"/>
<path d="M222.2 83.8l-2.5 2.6h-7.6M222.2 94l-2.5 2.5h-7.6M237.5 96.5l2.5 2.6h10.2M237.5 86.4l2.5 2.5h10.2M237.5 91.4l2.5 2.6h10.2M237.5 88.9l2.5 2.5h10.2M237.5 81.3l2.5 2.5h10.2M237.5 99.1l2.5 2.5h10.2M237.5 83.8l2.5 2.6h10.2M237.5 94l2.5 2.5h10.2M41.9 114.3l2.5 2.5h6.4M41.9 116.8l2.5 2.6h6.4"/>
<path d="M41.9 106.7l2.5 2.5h6.4M41.9 104.1l2.5 2.6h6.4M41.9 119.4l2.5 2.5h6.4M41.9 109.2l2.5 2.6h6.4M41.9 111.8l2.5 2.5h6.4M90.2 114.3l-2.6 2.5h-6.3M90.2 106.7l-2.6 2.5h-6.3M90.2 104.1l-2.6 2.6h-6.3M90.2 119.4l-2.6 2.5h-6.3M90.2 109.2l-2.6 2.6h-6.3M90.2 111.8l-2.6 2.5h-6.3M90.2 101.6l-2.6 2.5h-6.3"/>
<path d="M123.2 105.4v1.3h10.1M125.7 101.6l2.6 2.5h5M133.3 109.2h-1.2v6.4h11.4M143.5 114.3v2.5M181.6 104.1l2.5 2.6h7.7M181.6 101.6l2.5 2.5h7.7M191.8 109.2h-1.3v6.4h11.4M201.9 114.3v2.5M237.5 114.3l2.5 2.5h10.2M237.5 116.8l2.5 2.6h10.2M237.5 106.7l2.5 2.5h10.2M237.5 104.1l2.5 2.6h10.2"/>
<path d="M237.5 119.4l2.5 2.5h10.2M237.5 109.2l2.5 2.6h10.2M237.5 111.8l2.5 2.5h10.2M237.5 101.6l2.5 2.5h10.2M27.9 139.7h22.9M41.9 129.5l2.5 2.6h6.4M41.9 132.1l2.5 2.5h6.4M41.9 121.9l2.5 2.6h6.4M41.9 127l2.5 2.5h6.4M81.3 139.7h15.2M81.3 132.1h15.2M81.3 134.6h15.2"/>
<path d="M90.2 121.9l-2.6 2.6h-6.3M90.2 124.5l-2.6 2.5h-6.3M237.5 121.9l2.5 2.6h10.2M250.2 132.1h-1.3v7.6M250.2 127h-21.6v-106.7h-196.9v119.4M250.2 129.5h-77.5v62.3h-124.4v-31.8M27.9 144.8h22.9M49.5 152.4v2.5h1.3M50.8 152.4h-3.8v1.3M81.3 142.2h15.2M81.3 144.8h15.2M81.3 149.9h15.2"/>
<path d="M81.3 154.9h15.2M81.3 157.5h15.2M26.7 165.1h24.1M26.7 162.6h24.1M81.3 165.1h15.2M81.3 162.6h15.2M81.3 160h15.2M81.3 167.6h15.2M66 180.3v1.3"/>
</g>
<g fill="#000084" stroke="#000084" stroke-width=".18">
<circle cx="222.2" cy="27.9" r=".46"/>
<circle cx="181.6" cy="27.9" r=".46"/>
<circle cx="125.7" cy="124.5" r=".46"/>
</g>
<g fill="#009600" stroke="#009600" stroke-width=".18">
<circle cx="198.1" cy="55.9" r=".46"/>
<circle cx="201.9" cy="115.6" r=".46"/>
<circle cx="143.5" cy="115.6" r=".46"/>
<circle cx="62.2" cy="45.7" r=".46"/>
<circle cx="139.7" cy="55.9" r=".46"/>
<circle cx="31.7" cy="139.7" r=".46"/>
<circle cx="49.5" cy="152.4" r=".46"/>
</g>
<use href="#words"/>
</svg>
